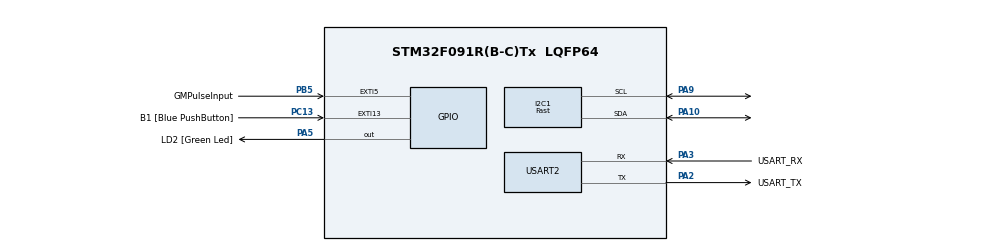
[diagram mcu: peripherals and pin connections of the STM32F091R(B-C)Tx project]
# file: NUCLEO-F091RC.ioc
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I2C1.I2C_Speed_Mode=I2C_Fast
I2C1.Timing=0x0000020B
Mcu.Family=STM32F0
Mcu.Name=STM32F091R(B-C)Tx
Mcu.Package=LQFP64
NVIC.EXTI4_15_IRQn=true\:0\:0\:false\:false\:true\:true
NVIC.TIM2_IRQn=true\:0\:0\:false\:false\:true\:true
PA10.Mode=I2C
PA10.Signal=I2C1_SDA
PA13.GPIO_Label=TMS
PA13.Mode=Serial_Wire
PA13.Signal=SYS_SWDIO
PA14.GPIO_Label=TCK
PA14.Mode=Serial_Wire
PA14.Signal=SYS_SWCLK
PA2.GPIO_Label=USART_TX
PA2.GPIO_Mode=GPIO_MODE_AF_PP
PA2.GPIO_PuPd=GPIO_NOPULL
PA2.GPIO_Speed=GPIO_SPEED_FREQ_LOW
PA2.Mode=Asynchronous
PA2.Signal=USART2_TX
PA3.GPIO_Label=USART_RX
PA3.GPIO_Mode=GPIO_MODE_AF_PP
PA3.GPIO_PuPd=GPIO_NOPULL
PA3.GPIO_Speed=GPIO_SPEED_FREQ_LOW
PA3.Mode=Asynchronous
PA3.Signal=USART2_RX
PA5.GPIO_Label=LD2 [Green Led]
PA5.GPIO_Mode=GPIO_MODE_OUTPUT_PP
PA5.GPIO_PuPd=GPIO_NOPULL
PA5.GPIO_Speed=GPIO_SPEED_FREQ_LOW
PA5.Signal=GPIO_Output
PA9.GPIO_FMA9=SYSCFG_CFGR1_I2C_FMP_PA9
PA9.Mode=I2C
PA9.Signal=I2C1_SCL
PB5.GPIO_Label=GMPulseInput
PB5.GPIO_ModeDefaultEXTI=GPIO_MODE_IT_FALLING
PB5.GPIO_PuPd=GPIO_PULLUP
PB5.Signal=GPXTI5
PC13.GPIO_Label=B1 [Blue PushButton]
PC13.GPIO_ModeDefaultEXTI=GPIO_MODE_IT_FALLING
PC13.Signal=GPXTI13
PC14OSC32_IN.Mode=LSE-External-Oscillator
PC14OSC32_IN.Signal=RCC_OSC32_IN
PC15OSC32_OUT.Mode=LSE-External-Oscillator
PC15OSC32_OUT.Signal=RCC_OSC32_OUT
PF0-OSC_IN.Mode=HSE-External-Clock-Source
PF0-OSC_IN.Signal=RCC_OSC_IN
PF1-OSC_OUT.Signal=RCC_OSC_OUT
ProjectManager.HeapSize=0x200
ProjectManager.StackSize=0x400
ProjectManager.TargetToolchain=SW4STM32
RCC.AHBFreq_Value=48000000
RCC.APB1Freq_Value=48000000
RCC.APB1TimFreq_Value=48000000
RCC.FLatency-AdvancedSettings=FLASH_LATENCY_1
RCC.HCLKFreq_Value=48000000
RCC.PLLDivider=RCC_PREDIV_DIV2
RCC.PLLMUL=RCC_PLL_MUL12
RCC.PREFETCH_ENABLE-AdvancedSettings=1
RCC.SYSCLKFreq_VALUE=48000000
RCC.SYSCLKSource=RCC_SYSCLKSOURCE_PLLCLK
TIM2.ClockDivision=TIM_CLOCKDIVISION_DIV4
TIM2.CounterMode=TIM_COUNTERMODE_DOWN
TIM2.Period=1
TIM2.Prescaler=100
USART2.VirtualMode=VM_ASYNC
USART2.VirtualMode-Asynchronous=VM_ASYNC
VP_TIM2_VS_ClockSourceINT.Mode=Internal
board=NUCLEO-F091RC

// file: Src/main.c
/* USER CODE BEGIN Header */
/**
  ******************************************************************************
  * @file           : main.c
  * @brief          : Main program body
  ******************************************************************************
  ** This notice applies to any and all portions of this file
  * that are not between comment pairs USER CODE BEGIN and
  * USER CODE END. Other portions of this file, whether
  * inserted by the user or by software development tools
  * are owned by their respective copyright owners.
  *
  * COPYRIGHT(c) 2020 STMicroelectronics
  *
  * Redistribution and use in source and binary forms, with or without modification,
  * are permitted provided that the following conditions are met:
  *   1. Redistributions of source code must retain the above copyright notice,
  *      this list of conditions and the following disclaimer.
  *   2. Redistributions in binary form must reproduce the above copyright notice,
  *      this list of conditions and the following disclaimer in the documentation
  *      and/or other materials provided with the distribution.
  *   3. Neither the name of STMicroelectronics nor the names of its contributors
  *      may be used to endorse or promote products derived from this software
  *      without specific prior written permission.
  *
  * THIS SOFTWARE IS PROVIDED BY THE COPYRIGHT HOLDERS AND CONTRIBUTORS "AS IS"
  * AND ANY EXPRESS OR IMPLIED WARRANTIES, INCLUDING, BUT NOT LIMITED TO, THE
  * IMPLIED WARRANTIES OF MERCHANTABILITY AND FITNESS FOR A PARTICULAR PURPOSE ARE
  * DISCLAIMED. IN NO EVENT SHALL THE COPYRIGHT HOLDER OR CONTRIBUTORS BE LIABLE
  * FOR ANY DIRECT, INDIRECT, INCIDENTAL, SPECIAL, EXEMPLARY, OR CONSEQUENTIAL
  * DAMAGES (INCLUDING, BUT NOT LIMITED TO, PROCUREMENT OF SUBSTITUTE GOODS OR
  * SERVICES; LOSS OF USE, DATA, OR PROFITS; OR BUSINESS INTERRUPTION) HOWEVER
  * CAUSED AND ON ANY THEORY OF LIABILITY, WHETHER IN CONTRACT, STRICT LIABILITY,
  * OR TORT (INCLUDING NEGLIGENCE OR OTHERWISE) ARISING IN ANY WAY OUT OF THE USE
  * OF THIS SOFTWARE, EVEN IF ADVISED OF THE POSSIBILITY OF SUCH DAMAGE.
  *
  ******************************************************************************
  */
/* USER CODE END Header */

#include "main.h"

/* USER CODE BEGIN Includes */
#include "gm_circular_buffer.h"
#include "gm_display_updater.h"
#include "gm_display_hw.h"
#include "gm_measurement_calculator.h"
#include "gm_logger.h"
/* USER CODE END Includes */

I2C_HandleTypeDef hi2c1;

TIM_HandleTypeDef htim2;

UART_HandleTypeDef huart2;

void SystemClock_Config(void);
static void MX_GPIO_Init(void);
static void MX_USART2_UART_Init(void);
static void MX_TIM2_Init(void);
static void MX_I2C1_Init(void);

int main(void)
{

  /* MCU Configuration--------------------------------------------------------*/

  /* Reset of all peripherals, Initializes the Flash interface and the Systick. */
  HAL_Init();

  /* Configure the system clock */
  SystemClock_Config();

  /* Initialize all configured peripherals */
  MX_GPIO_Init();
  MX_USART2_UART_Init();
  MX_TIM2_Init();
  MX_I2C1_Init();
  /* USER CODE BEGIN 2 */

  // TODO maybe add some module like ApplicationBuilder?
  GMCircularBuffer_Init();
  GMDisplayUpdater_Init();
  GMDisplayHW_Init();
  GMMeasurementCalculator_Init();
  GMLogger_Init();

  HAL_TIM_Base_Start_IT(&htim2);      //start timer2 in interrupt mode.

  /* USER CODE END 2 */

  /* Infinite loop */
  while (1)
  {

  }
}

void SystemClock_Config(void)
{
  RCC_OscInitTypeDef RCC_OscInitStruct = {0};
  RCC_ClkInitTypeDef RCC_ClkInitStruct = {0};
  RCC_PeriphCLKInitTypeDef PeriphClkInit = {0};

  /**Initializes the CPU, AHB and APB busses clocks
  */
  RCC_OscInitStruct.OscillatorType = RCC_OSCILLATORTYPE_HSI;
  RCC_OscInitStruct.HSIState = RCC_HSI_ON;
  RCC_OscInitStruct.HSICalibrationValue = RCC_HSICALIBRATION_DEFAULT;
  RCC_OscInitStruct.PLL.PLLState = RCC_PLL_ON;
  RCC_OscInitStruct.PLL.PLLSource = RCC_PLLSOURCE_HSI;
  RCC_OscInitStruct.PLL.PLLMUL = RCC_PLL_MUL2;
  RCC_OscInitStruct.PLL.PREDIV = RCC_PREDIV_DIV1;
  if (HAL_RCC_OscConfig(&RCC_OscInitStruct) != HAL_OK)
  {
    Error_Handler();
  }
  /**Initializes the CPU, AHB and APB busses clocks
  */
  RCC_ClkInitStruct.ClockType = RCC_CLOCKTYPE_HCLK|RCC_CLOCKTYPE_SYSCLK
                              |RCC_CLOCKTYPE_PCLK1;
  RCC_ClkInitStruct.SYSCLKSource = RCC_SYSCLKSOURCE_PLLCLK;
  RCC_ClkInitStruct.AHBCLKDivider = RCC_SYSCLK_DIV1;
  RCC_ClkInitStruct.APB1CLKDivider = RCC_HCLK_DIV1;

  if (HAL_RCC_ClockConfig(&RCC_ClkInitStruct, FLASH_LATENCY_0) != HAL_OK)
  {
    Error_Handler();
  }
  PeriphClkInit.PeriphClockSelection = RCC_PERIPHCLK_USART2|RCC_PERIPHCLK_I2C1;
  PeriphClkInit.Usart2ClockSelection = RCC_USART2CLKSOURCE_PCLK1;
  PeriphClkInit.I2c1ClockSelection = RCC_I2C1CLKSOURCE_HSI;
  if (HAL_RCCEx_PeriphCLKConfig(&PeriphClkInit) != HAL_OK)
  {
    Error_Handler();
  }
}

static void MX_I2C1_Init(void)
{

  hi2c1.Instance = I2C1;
  hi2c1.Init.Timing = 0x0000020B;
  hi2c1.Init.OwnAddress1 = 0;
  hi2c1.Init.AddressingMode = I2C_ADDRESSINGMODE_7BIT;
  hi2c1.Init.DualAddressMode = I2C_DUALADDRESS_DISABLE;
  hi2c1.Init.OwnAddress2 = 0;
  hi2c1.Init.OwnAddress2Masks = I2C_OA2_NOMASK;
  hi2c1.Init.GeneralCallMode = I2C_GENERALCALL_DISABLE;
  hi2c1.Init.NoStretchMode = I2C_NOSTRETCH_DISABLE;
  if (HAL_I2C_Init(&hi2c1) != HAL_OK)
  {
    Error_Handler();
  }
  /**Configure Analogue filter
  */
  if (HAL_I2CEx_ConfigAnalogFilter(&hi2c1, I2C_ANALOGFILTER_ENABLE) != HAL_OK)
  {
    Error_Handler();
  }
  /**Configure Digital filter
  */
  if (HAL_I2CEx_ConfigDigitalFilter(&hi2c1, 0) != HAL_OK)
  {
    Error_Handler();
  }

}

static void MX_TIM2_Init(void)
{

  TIM_ClockConfigTypeDef sClockSourceConfig = {0};
  TIM_MasterConfigTypeDef sMasterConfig = {0};

  htim2.Instance = TIM2;
  htim2.Init.Prescaler = 65534;
  htim2.Init.CounterMode = TIM_COUNTERMODE_UP;
  htim2.Init.Period = 14639;
  htim2.Init.ClockDivision = TIM_CLOCKDIVISION_DIV1;
  htim2.Init.AutoReloadPreload = TIM_AUTORELOAD_PRELOAD_DISABLE;
  if (HAL_TIM_Base_Init(&htim2) != HAL_OK)
  {
    Error_Handler();
  }
  sClockSourceConfig.ClockSource = TIM_CLOCKSOURCE_INTERNAL;
  if (HAL_TIM_ConfigClockSource(&htim2, &sClockSourceConfig) != HAL_OK)
  {
    Error_Handler();
  }
  sMasterConfig.MasterOutputTrigger = TIM_TRGO_RESET;
  sMasterConfig.MasterSlaveMode = TIM_MASTERSLAVEMODE_DISABLE;
  if (HAL_TIMEx_MasterConfigSynchronization(&htim2, &sMasterConfig) != HAL_OK)
  {
    Error_Handler();
  }

}

static void MX_USART2_UART_Init(void)
{

  huart2.Instance = USART2;
  huart2.Init.BaudRate = 115200;
  huart2.Init.WordLength = UART_WORDLENGTH_8B;
  huart2.Init.StopBits = UART_STOPBITS_1;
  huart2.Init.Parity = UART_PARITY_NONE;
  huart2.Init.Mode = UART_MODE_TX_RX;
  huart2.Init.HwFlowCtl = UART_HWCONTROL_NONE;
  huart2.Init.OverSampling = UART_OVERSAMPLING_16;
  huart2.Init.OneBitSampling = UART_ONE_BIT_SAMPLE_DISABLE;
  huart2.AdvancedInit.AdvFeatureInit = UART_ADVFEATURE_NO_INIT;
  if (HAL_UART_Init(&huart2) != HAL_OK)
  {
    Error_Handler();
  }

}

static void MX_GPIO_Init(void)
{
  GPIO_InitTypeDef GPIO_InitStruct = {0};

  /* GPIO Ports Clock Enable */
  __HAL_RCC_GPIOC_CLK_ENABLE();
  __HAL_RCC_GPIOF_CLK_ENABLE();
  __HAL_RCC_GPIOA_CLK_ENABLE();
  __HAL_RCC_GPIOB_CLK_ENABLE();

  /*Configure GPIO pin Output Level */
  HAL_GPIO_WritePin(LD2_GPIO_Port, LD2_Pin, GPIO_PIN_RESET);

  /*Configure GPIO pin : B1_Pin */
  GPIO_InitStruct.Pin = B1_Pin;
  GPIO_InitStruct.Mode = GPIO_MODE_IT_FALLING;
  GPIO_InitStruct.Pull = GPIO_NOPULL;
  HAL_GPIO_Init(B1_GPIO_Port, &GPIO_InitStruct);

  /*Configure GPIO pin : LD2_Pin */
  GPIO_InitStruct.Pin = LD2_Pin;
  GPIO_InitStruct.Mode = GPIO_MODE_OUTPUT_PP;
  GPIO_InitStruct.Pull = GPIO_NOPULL;
  GPIO_InitStruct.Speed = GPIO_SPEED_FREQ_LOW;
  HAL_GPIO_Init(LD2_GPIO_Port, &GPIO_InitStruct);

  /*Configure GPIO pin : GMPulseInput_Pin */
  GPIO_InitStruct.Pin = GMPulseInput_Pin;
  GPIO_InitStruct.Mode = GPIO_MODE_IT_FALLING;
  GPIO_InitStruct.Pull = GPIO_PULLUP;
  HAL_GPIO_Init(GMPulseInput_GPIO_Port, &GPIO_InitStruct);

  /* EXTI interrupt init*/
  HAL_NVIC_SetPriority(EXTI4_15_IRQn, 0, 0);
  HAL_NVIC_EnableIRQ(EXTI4_15_IRQn);

}

void Error_Handler(void)
{
}

/************************ (C) COPYRIGHT STMicroelectronics *****END OF FILE****/
